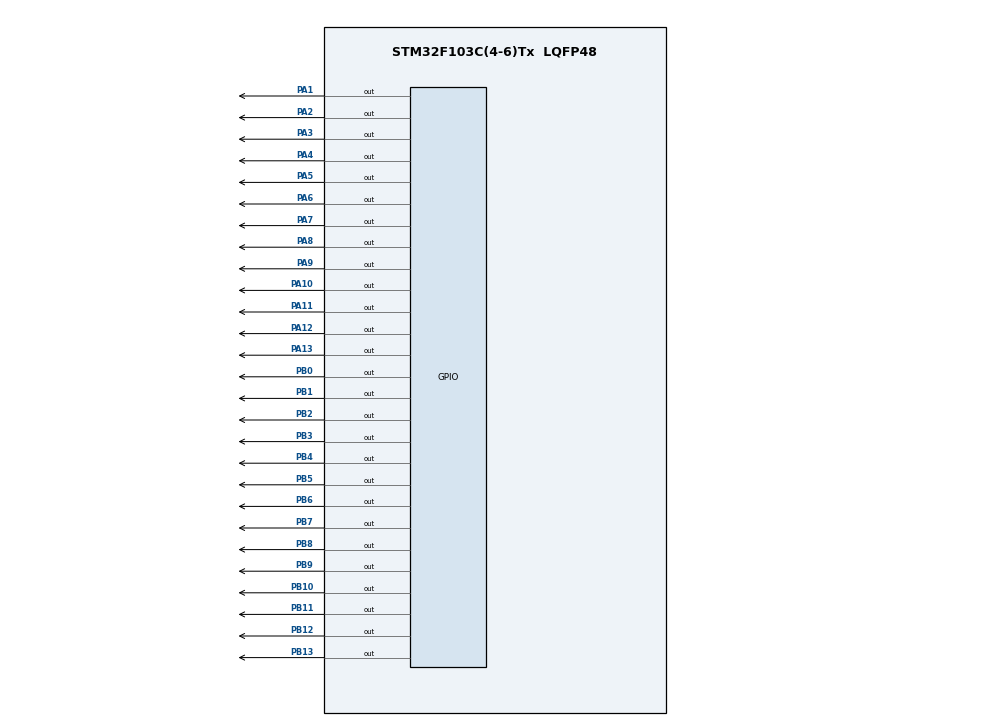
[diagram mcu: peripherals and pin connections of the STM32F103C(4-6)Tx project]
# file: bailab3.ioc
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Mcu.Family=STM32F1
Mcu.Name=STM32F103C(4-6)Tx
Mcu.Package=LQFP48
NVIC.PriorityGroup=NVIC_PRIORITYGROUP_4
NVIC.TIM2_IRQn=true\:0\:0\:false\:false\:true\:true\:true
PA1.Signal=GPIO_Output
PA10.Signal=GPIO_Output
PA11.Signal=GPIO_Output
PA12.Signal=GPIO_Output
PA13.Signal=GPIO_Output
PA2.Signal=GPIO_Output
PA3.Signal=GPIO_Output
PA4.Signal=GPIO_Output
PA5.Signal=GPIO_Output
PA6.Signal=GPIO_Output
PA7.Signal=GPIO_Output
PA8.Signal=GPIO_Output
PA9.Signal=GPIO_Output
PB0.Signal=GPIO_Output
PB1.Signal=GPIO_Output
PB10.Signal=GPIO_Output
PB11.Signal=GPIO_Output
PB12.Signal=GPIO_Output
PB13.Signal=GPIO_Output
PB2.Signal=GPIO_Output
PB3.Signal=GPIO_Output
PB4.Signal=GPIO_Output
PB5.Signal=GPIO_Output
PB6.Signal=GPIO_Output
PB7.Signal=GPIO_Output
PB8.Signal=GPIO_Output
PB9.Signal=GPIO_Output
PD0-OSC_IN.Mode=HSE-External-Oscillator
PD0-OSC_IN.Signal=RCC_OSC_IN
PD1-OSC_OUT.Mode=HSE-External-Oscillator
PD1-OSC_OUT.Signal=RCC_OSC_OUT
ProjectManager.HeapSize=0x200
ProjectManager.StackSize=0x400
ProjectManager.TargetToolchain=STM32CubeIDE
RCC.APB1Freq_Value=8000000
RCC.APB2Freq_Value=8000000
TIM2.Period=9
TIM2.Prescaler=7999
VP_SYS_VS_ND.Mode=No_Debug
VP_TIM2_VS_ClockSourceINT.Mode=Internal
board=custom

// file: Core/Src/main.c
/* USER CODE BEGIN Header */
/**
  ******************************************************************************
  * @file           : main.c
  * @brief          : Main program body
  ******************************************************************************
  * @attention
  *
  * <h2><center>&copy; Copyright (c) 2021 STMicroelectronics.
  * All rights reserved.</center></h2>
  *
  * This software component is licensed by ST under BSD 3-Clause license,
  * the "License"; You may not use this file except in compliance with the
  * License. You may obtain a copy of the License at:
  *                        opensource.org/licenses/BSD-3-Clause
  *
  ******************************************************************************
  */
/* USER CODE END Header */
#include "main.h"
/* USER CODE BEGIN Includes */
#include "global.h"
#include "input_processing.h"
/* USER CODE END Includes */

TIM_HandleTypeDef htim2;

void SystemClock_Config(void);
static void MX_GPIO_Init(void);
static void MX_TIM2_Init(void);

int main(void)
{

  /* MCU Configuration--------------------------------------------------------*/

  /* Reset of all peripherals, Initializes the Flash interface and the Systick. */
  HAL_Init();

  /* Configure the system clock */
  SystemClock_Config();

  /* Initialize all configured peripherals */
  MX_GPIO_Init();
  MX_TIM2_Init();
  /* USER CODE BEGIN 2 */
  HAL_TIM_Base_Start_IT(&htim2);
  setTimer0(10);
  setTimer1(10);
  /* USER CODE END 2 */

  /* Infinite loop */
  while (1)
  {
	  	  fsm_for_button0();
	  	  fsm_for_button1();
	  	  fsm_for_button2();
	  	  fsm_modify_mode();
	  	  if(timer0_flag == 1){
	  		  fsm_traffic_light();
	  		  setTimer0(1000);
	  	  }
	  	  if(timer1_flag == 1){
	  		  fsm_blinking_led();
	  		  fsm_display_7SEG();
	  		  setTimer1(250);
	  	  }
  }
}

void SystemClock_Config(void)
{
  RCC_OscInitTypeDef RCC_OscInitStruct = {0};
  RCC_ClkInitTypeDef RCC_ClkInitStruct = {0};

  /** Initializes the RCC Oscillators according to the specified parameters
  * in the RCC_OscInitTypeDef structure.
  */
  RCC_OscInitStruct.OscillatorType = RCC_OSCILLATORTYPE_HSI;
  RCC_OscInitStruct.HSIState = RCC_HSI_ON;
  RCC_OscInitStruct.HSICalibrationValue = RCC_HSICALIBRATION_DEFAULT;
  RCC_OscInitStruct.PLL.PLLState = RCC_PLL_NONE;
  if (HAL_RCC_OscConfig(&RCC_OscInitStruct) != HAL_OK)
  {
    Error_Handler();
  }
  /** Initializes the CPU, AHB and APB buses clocks
  */
  RCC_ClkInitStruct.ClockType = RCC_CLOCKTYPE_HCLK|RCC_CLOCKTYPE_SYSCLK
                              |RCC_CLOCKTYPE_PCLK1|RCC_CLOCKTYPE_PCLK2;
  RCC_ClkInitStruct.SYSCLKSource = RCC_SYSCLKSOURCE_HSI;
  RCC_ClkInitStruct.AHBCLKDivider = RCC_SYSCLK_DIV1;
  RCC_ClkInitStruct.APB1CLKDivider = RCC_HCLK_DIV1;
  RCC_ClkInitStruct.APB2CLKDivider = RCC_HCLK_DIV1;

  if (HAL_RCC_ClockConfig(&RCC_ClkInitStruct, FLASH_LATENCY_0) != HAL_OK)
  {
    Error_Handler();
  }
}

static void MX_TIM2_Init(void)
{

  TIM_ClockConfigTypeDef sClockSourceConfig = {0};
  TIM_MasterConfigTypeDef sMasterConfig = {0};

  htim2.Instance = TIM2;
  htim2.Init.Prescaler = 8000-1;
  htim2.Init.CounterMode = TIM_COUNTERMODE_UP;
  htim2.Init.Period = 10-1;
  htim2.Init.ClockDivision = TIM_CLOCKDIVISION_DIV1;
  htim2.Init.AutoReloadPreload = TIM_AUTORELOAD_PRELOAD_DISABLE;
  if (HAL_TIM_Base_Init(&htim2) != HAL_OK)
  {
    Error_Handler();
  }
  sClockSourceConfig.ClockSource = TIM_CLOCKSOURCE_INTERNAL;
  if (HAL_TIM_ConfigClockSource(&htim2, &sClockSourceConfig) != HAL_OK)
  {
    Error_Handler();
  }
  sMasterConfig.MasterOutputTrigger = TIM_TRGO_RESET;
  sMasterConfig.MasterSlaveMode = TIM_MASTERSLAVEMODE_DISABLE;
  if (HAL_TIMEx_MasterConfigSynchronization(&htim2, &sMasterConfig) != HAL_OK)
  {
    Error_Handler();
  }

}

static void MX_GPIO_Init(void)
{
  GPIO_InitTypeDef GPIO_InitStruct = {0};

  /* GPIO Ports Clock Enable */
  __HAL_RCC_GPIOA_CLK_ENABLE();
  __HAL_RCC_GPIOB_CLK_ENABLE();

  /*Configure GPIO pin Output Level */
  HAL_GPIO_WritePin(GPIOA, LEDR0_Pin|LEDY0_Pin|LEDG0_Pin|LEDR1_Pin
                          |LEDY1_Pin|LEDG1_Pin|EN0_Pin|EN1_Pin
                          |EN2_Pin|EN3_Pin, GPIO_PIN_RESET);

  /*Configure GPIO pin Output Level */
  HAL_GPIO_WritePin(GPIOB, SEG0_0_Pin|SEG0_1_Pin|SEG0_2_Pin|SEG1_3_Pin
                          |SEG1_4_Pin|SEG1_5_Pin|SEG1_6_Pin|SEG0_3_Pin
                          |SEG0_4_Pin|SEG0_5_Pin|SEG0_6_Pin|SEG1_0_Pin
                          |SEG1_1_Pin|SEG1_2_Pin, GPIO_PIN_RESET);

  /*Configure GPIO pins : LEDR0_Pin LEDY0_Pin LEDG0_Pin LEDR1_Pin
                           LEDY1_Pin LEDG1_Pin EN0_Pin EN1_Pin
                           EN2_Pin EN3_Pin */
  GPIO_InitStruct.Pin = LEDR0_Pin|LEDY0_Pin|LEDG0_Pin|LEDR1_Pin
                          |LEDY1_Pin|LEDG1_Pin|EN0_Pin|EN1_Pin
                          |EN2_Pin|EN3_Pin;
  GPIO_InitStruct.Mode = GPIO_MODE_OUTPUT_PP;
  GPIO_InitStruct.Pull = GPIO_NOPULL;
  GPIO_InitStruct.Speed = GPIO_SPEED_FREQ_LOW;
  HAL_GPIO_Init(GPIOA, &GPIO_InitStruct);

  /*Configure GPIO pins : SEG0_0_Pin SEG0_1_Pin SEG0_2_Pin SEG1_3_Pin
                           SEG1_4_Pin SEG1_5_Pin SEG1_6_Pin SEG0_3_Pin
                           SEG0_4_Pin SEG0_5_Pin SEG0_6_Pin SEG1_0_Pin
                           SEG1_1_Pin SEG1_2_Pin */
  GPIO_InitStruct.Pin = SEG0_0_Pin|SEG0_1_Pin|SEG0_2_Pin|SEG1_3_Pin
                          |SEG1_4_Pin|SEG1_5_Pin|SEG1_6_Pin|SEG0_3_Pin
                          |SEG0_4_Pin|SEG0_5_Pin|SEG0_6_Pin|SEG1_0_Pin
                          |SEG1_1_Pin|SEG1_2_Pin;
  GPIO_InitStruct.Mode = GPIO_MODE_OUTPUT_PP;
  GPIO_InitStruct.Pull = GPIO_NOPULL;
  GPIO_InitStruct.Speed = GPIO_SPEED_FREQ_LOW;
  HAL_GPIO_Init(GPIOB, &GPIO_InitStruct);

  /*Configure GPIO pins : BUTTON0_Pin BUTTON1_Pin BUTTON2_Pin */
  GPIO_InitStruct.Pin = BUTTON0_Pin|BUTTON1_Pin|BUTTON2_Pin;
  GPIO_InitStruct.Mode = GPIO_MODE_INPUT;
  GPIO_InitStruct.Pull = GPIO_NOPULL;
  HAL_GPIO_Init(GPIOA, &GPIO_InitStruct);

}

void Error_Handler(void)
{
  __disable_irq();
  while (1)
  {
  }
}

/************************ (C) COPYRIGHT STMicroelectronics *****END OF FILE****/
